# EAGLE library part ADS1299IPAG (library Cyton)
Low-Noise, 8-Channel, 24-Bit Analog-to-Digital Converter for Biopotential Measurements Source: Datasheet

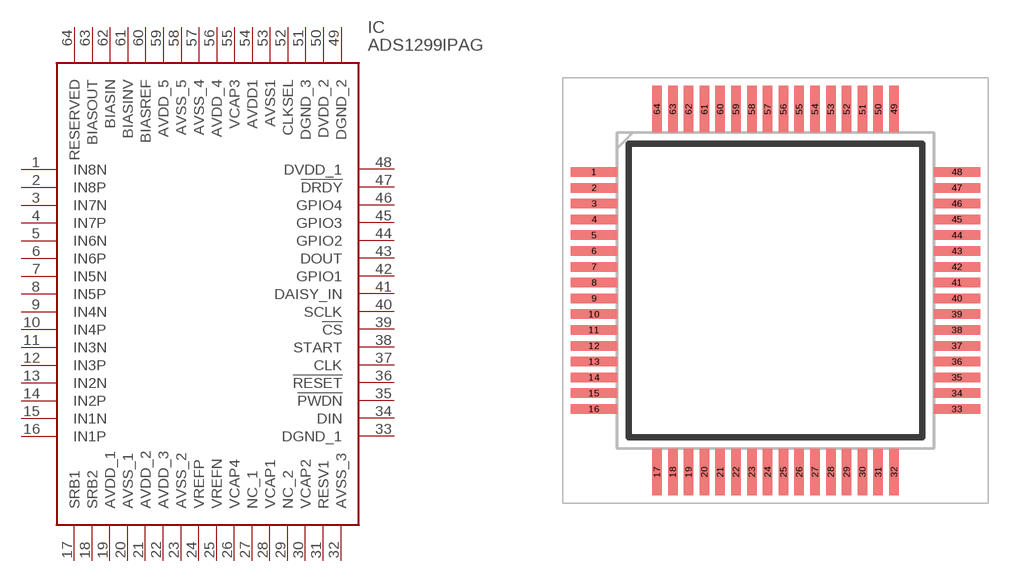
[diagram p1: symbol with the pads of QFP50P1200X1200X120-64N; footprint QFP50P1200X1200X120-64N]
Designator prefix IC

## ADS1299IPAG (DESCRIPTION: Low-Noise, 8-Channel, 24-Bit Analog-to-Digital Converter for Biopotential Measurements; HEIGHT: 1.2mm; MANUFACTURER_NAME: Texas Instruments; MANUFACTURER_PART_NUMBER: ADS1299IPAG)  [QFP50P1200X1200X120-64N]
1  IN8N
2  IN8P
3  IN7N
4  IN7P
5  IN6N
6  IN6P
7  IN5N
8  IN5P
9  IN4N
10  IN4P
11  IN3N
12  IN3P
13  IN2N
14  IN2P
15  IN1N
16  IN1P
17  SRB1
18  SRB2
19  AVDD_1
20  AVSS_1
21  AVDD_2
22  AVDD_3
23  AVSS_2
24  VREFP
25  VREFN
26  VCAP4
27  NC_1
28  VCAP1
29  NC_2
30  VCAP2
31  RESV1
32  AVSS_3
33  DGND_1
34  DIN
35  !PWDN
36  !RESET
37  CLK
38  START
39  !CS
40  SCLK
41  DAISY_IN
42  GPIO1
43  DOUT
44  GPIO2
45  GPIO3
46  GPIO4
47  !DRDY
48  DVDD_1
49  DGND_2
50  DVDD_2
51  DGND_3
52  CLKSEL
53  AVSS1
54  AVDD1
55  VCAP3
56  AVDD_4
57  AVSS_4
58  AVSS_5
59  AVDD_5
60  BIASREF
61  BIASINV
62  BIASIN
63  BIASOUT
64  RESERVED

## Footprint QFP50P1200X1200X120-64N (pad centres in mm)
PAG (S-PQFP-G64)
smd 1.475 x 0.3: 1 -5.738,3.75; 2 -5.738,3.25; 3 -5.738,2.75; 4 -5.738,2.25; 5 -5.738,1.75; 6 -5.738,1.25; 7 -5.738,0.75; 8 -5.738,0.25; 9 -5.738,-0.25; 10 -5.738,-0.75; 11 -5.738,-1.25; 12 -5.738,-1.75; 13 -5.738,-2.25; 14 -5.738,-2.75; 15 -5.738,-3.25; 16 -5.738,-3.75; 33 5.738,-3.75; 34 5.738,-3.25; 35 5.738,-2.75; 36 5.738,-2.25; 37 5.738,-1.75; 38 5.738,-1.25; 39 5.738,-0.75; 40 5.738,-0.25; 41 5.738,0.25; 42 5.738,0.75; 43 5.738,1.25; 44 5.738,1.75; 45 5.738,2.25; 46 5.738,2.75; 47 5.738,3.25; 48 5.738,3.75
smd 0.3 x 1.475: 17 -3.75,-5.738; 18 -3.25,-5.738; 19 -2.75,-5.738; 20 -2.25,-5.738; 21 -1.75,-5.738; 22 -1.25,-5.738; 23 -0.75,-5.738; 24 -0.25,-5.738; 25 0.25,-5.738; 26 0.75,-5.738; 27 1.25,-5.738; 28 1.75,-5.738; 29 2.25,-5.738; 30 2.75,-5.738; 31 3.25,-5.738; 32 3.75,-5.738; 49 3.75,5.738; 50 3.25,5.738; 51 2.75,5.738; 52 2.25,5.738; 53 1.75,5.738; 54 1.25,5.738; 55 0.75,5.738; 56 0.25,5.738; 57 -0.25,5.738; 58 -0.75,5.738; 59 -1.25,5.738; 60 -1.75,5.738; 61 -2.25,5.738; 62 -2.75,5.738; 63 -3.25,5.738; 64 -3.75,5.738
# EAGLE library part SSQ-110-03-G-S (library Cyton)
CONN SOCKET, 2.54MM, THT VERT, 10POS Source: Datasheet

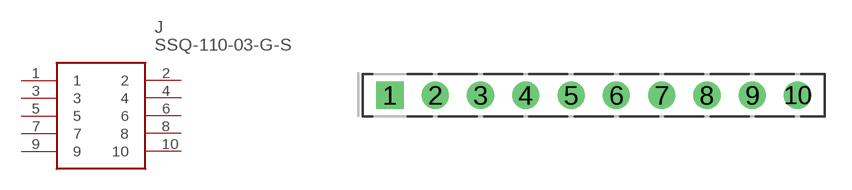
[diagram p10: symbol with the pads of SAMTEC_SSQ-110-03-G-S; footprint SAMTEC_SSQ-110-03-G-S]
Designator prefix J

## SSQ-110-03-G-S (DESCRIPTION: CONN SOCKET, 2.54MM, THT VERT, 10POS; HEIGHT: mm; MANUFACTURER_NAME: SAMTEC; MANUFACTURER_PART_NUMBER: SSQ-110-03-G-S; MOUSER_PART_NUMBER: 200-SSQ11003GS; MOUSER_PRICE-STOCK: https://www.mouser.com/Search/Refine.aspx?Keyword=200-SSQ11003GS)  [SAMTEC_SSQ-110-03-G-S]
1  1
2  2
3  3
4  4
5  5
6  6
7  7
8  8
9  9
10  10

## Footprint SAMTEC_SSQ-110-03-G-S (pad centres in mm)
SAMTEC_SSQ-110-03-G-S
drill 1.016 pad 1.524 square: 1 -22.86,0
drill 1.016 pad 1.524: 2 -20.32,0; 3 -17.78,0; 4 -15.24,0; 5 -12.7,0; 6 -10.16,0; 7 -7.62,0; 8 -5.08,0; 9 -2.54,0; 10 0,0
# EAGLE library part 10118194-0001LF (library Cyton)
Micro Usb, 2.0 Type b, Rcpt, Smt

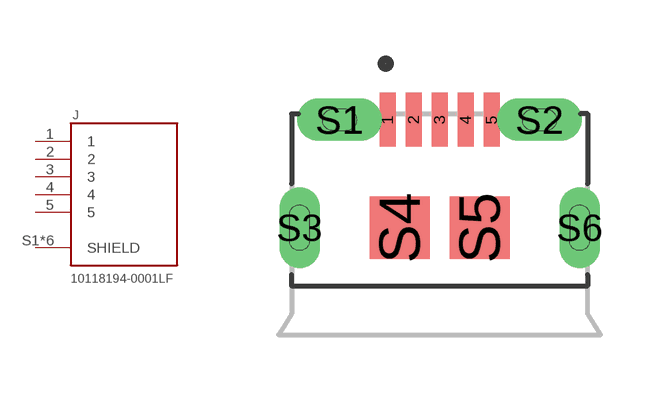
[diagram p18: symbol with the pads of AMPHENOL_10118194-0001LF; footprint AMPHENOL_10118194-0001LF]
Designator prefix J

## 10118194-0001LF (AVAILABILITY: Unavailable; DESCRIPTION: USB - micro B USB 2.0 Receptacle Connector 5 Position Surface Mount, Right Angle; Through Hole; MF: Amphenol ICC; MP: 10118194-0001LF; PACKAGE: None; PRICE: None)  [AMPHENOL_10118194-0001LF]
1  1  pas
2  2  pas
3  3  pas
4  4  pas
5  5  pas
S1  SHIELD  pas
S2  SHIELD  pas
S3  SHIELD  pas
S4  SHIELD  pas
S5  SHIELD  pas
S6  SHIELD  pas

## Footprint AMPHENOL_10118194-0001LF (pad centres in mm)
smd 0.4 x 1.35: 1 -1.3,2.7; 2 -0.65,2.7; 3 0,2.7; 4 0.65,2.7; 5 1.3,2.7
drill 0.55 pad 0.61 long: S1 -2.5,2.7; S2 2.5,2.7
drill 0.5 pad 0.775 long: S3 -3.5,0; S6 3.5,0
smd 1.5 x 1.55: S4 -1,0; S5 1,0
